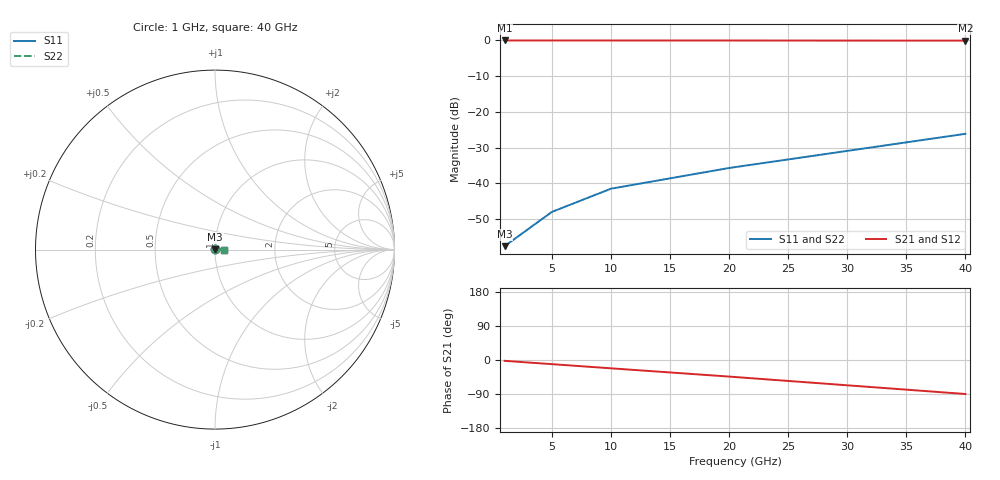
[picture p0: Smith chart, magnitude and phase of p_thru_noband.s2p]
! Generated by circuitRF - EM: Full-wave planar
! circuitRF-EM setup: p_thru
! circuitRF-EM layout: thru/layout/thru.clay
! circuitRF-EM written: 2026-11-04 23:02:35Z
! circuitRF-EM geometry: 4a11a80c9c386502
! circuitRF-EM mesh: 025622186bca0020
! circuitRF-EM ports: 5bce169309c672a4
! circuitRF-EM model: grounded-edge-port-2026-10-14
! Port[1] = 1
! Port[2] = 2
! circuitRF-EM port 1: '1' at (0, 0 um), edge, de-embedded, 50 Ohm
! circuitRF-EM port 2: '2' at (640, 0 um), edge, de-embedded, 50 Ohm
! circuitRF-EM: port N of this file is the label named on the 'port N' line above. A circuit that composes this result binds its nets in that order; two ports of a reciprocal part swapped gives a plausible curve of a different structure.
! circuitRF-EM: re-running the EM setup rewrites this file. If circuitRF reports it as stale, the layout's cross-section changed after this file was written.
# GHz S RI R 50
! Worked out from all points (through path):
!   5 points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, 1 GHz to 40 GHz, reference 50 ohm
!   highest |S21| = -0.01 dB at 1 GHz (marker M1); lowest = -0.1 dB at 40 GHz (marker M2)
!   lowest |S11| = -57.6 dB at 1 GHz (marker M3), VSWR 1.00, Z = 50.1 + j0.0637 ohm
!   |S11| at or under -10 dB: start of sweep to end of sweep
!   |S22| runs from -57.6 to -26.1 dB; largest |S21 - S12| = 1.7e-09
1  0.00116 0.000636  0.9981 -0.0382  0.9981 -0.0382  0.00116 0.000636
5  0.0021 0.00339  0.9804 -0.19  0.9804 -0.19  0.0021 0.00339
10  0.00498 0.00679  0.9258 -0.3727  0.9258 -0.3727  0.00498 0.00679
20  0.0133 0.00958  0.7204 -0.69  0.7204 -0.69  0.0133 0.00959
40  0.0492 -0.00362  0.00451 -0.9928  0.00451 -0.9928  0.0492 -0.00382
